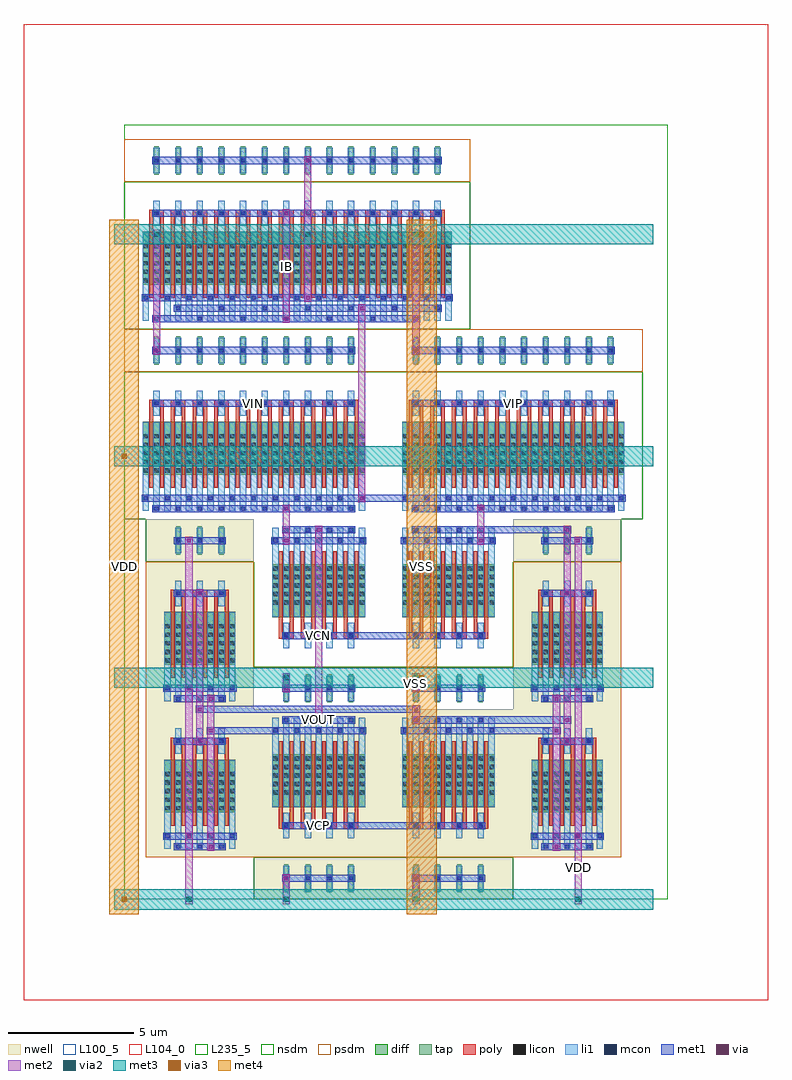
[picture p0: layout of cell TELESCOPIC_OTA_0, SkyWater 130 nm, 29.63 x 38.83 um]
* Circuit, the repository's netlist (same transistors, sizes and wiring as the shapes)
* NGSPICE file created from TELESCOPIC_OTA_0.ext - technology: sky130A

.subckt PMOS_S_26075639_X3_Y2_1774869254 a_230_357# a_200_252# w_0_0#
X0 a_230_357# a_200_252# w_0_0# w_0_0# sky130_fd_pr__pfet_01v8 ad=0.294 pd=2.38 as=0.5565 ps=4.73 w=2.1 l=0.15 M=12
.ends

.subckt SCM_NMOS_72619132_X7_Y1_1774869255 a_200_252# a_402_357# a_147_357#
X0 a_200_252# a_200_252# a_147_357# a_147_357# sky130_fd_pr__nfet_01v8 ad=0.294 pd=2.38 as=0.294 ps=2.38 w=2.1 l=0.15 M=14
X1 a_147_357# a_200_252# a_402_357# a_147_357# sky130_fd_pr__nfet_01v8 ad=0.294 pd=2.38 as=0.294 ps=2.38 w=2.1 l=0.15 M=14
.ends

.subckt NMOS_4T_1818045_X10_Y1_1774869251 a_230_357# a_200_252# a_147_357# a_241_1232#
X0 a_230_357# a_200_252# a_147_357# a_241_1232# sky130_fd_pr__nfet_01v8 ad=0.294 pd=2.38 as=0.294 ps=2.38 w=2.1 l=0.15 M=20
.ends

.subckt NMOS_4T_97331930_X4_Y1_1774869252 a_230_357# a_200_252# a_147_357# a_241_1232#
X0 a_230_357# a_200_252# a_147_357# a_241_1232# sky130_fd_pr__nfet_01v8 ad=0.294 pd=2.38 as=0.294 ps=2.38 w=2.1 l=0.15 M=8
.ends

.subckt PMOS_4T_28463424_X4_Y1_1774869253 a_230_357# a_200_252# a_147_357# w_0_0#
X0 a_230_357# a_200_252# a_147_357# w_0_0# sky130_fd_pr__pfet_01v8 ad=0.294 pd=2.38 as=0.5565 ps=4.73 w=2.1 l=0.15 M=8
.ends

.subckt TELESCOPIC_OTA_0 IB VCN VOUT VIP VIN VCP VSS VDD
XPMOS_S_26075639_X3_Y2_1774869254_0 m1_656_1316# m1_570_1484# VDD PMOS_S_26075639_X3_Y2_1774869254
XPMOS_S_26075639_X3_Y2_1774869254_1 m1_2924_1316# m1_570_1484# VDD PMOS_S_26075639_X3_Y2_1774869254
XSCM_NMOS_72619132_X7_Y1_1774869255_0 IB m1_1860_3164# VSS SCM_NMOS_72619132_X7_Y1_1774869255
XNMOS_4T_1818045_X10_Y1_1774869251_0 m1_1258_2828# VIN m1_1860_3164# VSS NMOS_4T_1818045_X10_Y1_1774869251
XNMOS_4T_1818045_X10_Y1_1774869251_1 m1_2806_2828# VIP m1_1860_3164# VSS NMOS_4T_1818045_X10_Y1_1774869251
XNMOS_4T_97331930_X4_Y1_1774869252_0 VOUT VCN m1_1258_2828# VSS NMOS_4T_97331930_X4_Y1_1774869252
XPMOS_4T_28463424_X4_Y1_1774869253_0 VOUT VCP m1_656_1316# VDD PMOS_4T_28463424_X4_Y1_1774869253
XNMOS_4T_97331930_X4_Y1_1774869252_1 m1_570_1484# VCN m1_2806_2828# VSS NMOS_4T_97331930_X4_Y1_1774869252
XPMOS_4T_28463424_X4_Y1_1774869253_1 m1_570_1484# VCP m1_2924_1316# VDD PMOS_4T_28463424_X4_Y1_1774869253
.ends

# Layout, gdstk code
from math import pi, radians
import gdstk
lib = gdstk.Library(unit=1e-6, precision=1e-09)
def R(c, l, rs):  # rectangles x0, y0, x1, y1
    for r in rs: c.add(gdstk.rectangle(r[:2], r[2:], *l))
def A(c, l, x, y, w, h, nx, ny, dx, dy):  # array of equal rectangles
    R(c, l, [(x+i*dx, y+j*dy, x+i*dx+w, y+j*dy+h) for i in range(nx) for j in range(ny)])
def P(c, l, *ps):  # polygons
    for p in ps: c.add(gdstk.Polygon(p, *l))
nwell = (64, 20)
diff = (65, 20)
tap = (65, 44)
poly = (66, 20)
licon = (66, 44)
li1 = (67, 20)
mcon = (67, 44)
met1 = (68, 20)
via = (68, 44)
met2 = (69, 20)
via2 = (69, 44)
met3 = (70, 20)
via3 = (70, 44)
met4 = (71, 20)
nsdm = (93, 44)
psdm = (94, 20)
L100_5 = (100, 5)
L104_0 = (104, 0)
L235_5 = (235, 5)

scm_nmos_72619132_x7_y1_ = lib.new_cell('SCM_NMOS_72619132_X7_Y1_1774869255')
R(scm_nmos_72619132_x7_y1_, diff, [(0.735,1.785,13.025,3.885)])
A(scm_nmos_72619132_x7_y1_, tap, 1.205, 6.16, 0.17, 1.12, 14, 1, 0.86, 0)
A(scm_nmos_72619132_x7_y1_, poly, 1, 1.26, 0.15, 3.36, 28, 1, 0.43, 0)
A(scm_nmos_72619132_x7_y1_, poly, 1, 4.485, 0.58, 0.27, 14, 1, 0.86, 0)
A(scm_nmos_72619132_x7_y1_, licon, 0.775, 1.865, 0.17, 0.17, 3, 5, 0.43, 0.34)
A(scm_nmos_72619132_x7_y1_, licon, 1.635, 1.865, 0.17, 0.17, 3, 5, 0.43, 0.34)
A(scm_nmos_72619132_x7_y1_, licon, 2.495, 1.865, 0.17, 0.17, 3, 5, 0.43, 0.34)
A(scm_nmos_72619132_x7_y1_, licon, 3.355, 1.865, 0.17, 0.17, 3, 5, 0.43, 0.34)
A(scm_nmos_72619132_x7_y1_, licon, 4.215, 1.865, 0.17, 0.17, 3, 5, 0.43, 0.34)
A(scm_nmos_72619132_x7_y1_, licon, 5.075, 1.865, 0.17, 0.17, 3, 5, 0.43, 0.34)
A(scm_nmos_72619132_x7_y1_, licon, 5.935, 1.865, 0.17, 0.17, 3, 5, 0.43, 0.34)
A(scm_nmos_72619132_x7_y1_, licon, 6.795, 1.865, 0.17, 0.17, 3, 5, 0.43, 0.34)
A(scm_nmos_72619132_x7_y1_, licon, 7.655, 1.865, 0.17, 0.17, 3, 5, 0.43, 0.34)
A(scm_nmos_72619132_x7_y1_, licon, 8.515, 1.865, 0.17, 0.17, 3, 5, 0.43, 0.34)
A(scm_nmos_72619132_x7_y1_, licon, 9.375, 1.865, 0.17, 0.17, 3, 5, 0.43, 0.34)
A(scm_nmos_72619132_x7_y1_, licon, 10.235, 1.865, 0.17, 0.17, 3, 5, 0.43, 0.34)
A(scm_nmos_72619132_x7_y1_, licon, 11.095, 1.865, 0.17, 0.17, 3, 5, 0.43, 0.34)
A(scm_nmos_72619132_x7_y1_, licon, 11.955, 1.865, 0.17, 0.17, 3, 5, 0.43, 0.34)
A(scm_nmos_72619132_x7_y1_, licon, 1.205, 4.535, 0.17, 0.17, 14, 2, 0.86, 2.1)
A(scm_nmos_72619132_x7_y1_, li1, 0.735, 0.335, 0.25, 3.53, 29, 1, 0.43, 0)
A(scm_nmos_72619132_x7_y1_, li1, 1.165, 4.115, 0.25, 1.01, 14, 2, 0.86, 2.1)
A(scm_nmos_72619132_x7_y1_, mcon, 1.205, 0.335, 0.17, 0.17, 7, 1, 1.72, 0)
A(scm_nmos_72619132_x7_y1_, mcon, 2.065, 0.755, 0.17, 0.17, 7, 1, 1.72, 0)
A(scm_nmos_72619132_x7_y1_, mcon, 0.775, 1.175, 0.17, 0.17, 15, 1, 0.86, 0)
A(scm_nmos_72619132_x7_y1_, mcon, 1.205, 4.535, 0.17, 0.17, 14, 2, 0.86, 2.1)
R(scm_nmos_72619132_x7_y1_, met1, [(1.12,0.28,11.78,0.56), (1.98,0.7,12.64,0.98), (0.69,1.12,13.07,1.4), (1.12,4.48,12.64,4.76), (1.12,6.58,12.64,6.86)])
R(scm_nmos_72619132_x7_y1_, via, [(6.375,0.345,6.525,0.495), (7.235,1.185,7.385,1.335), (6.375,4.545,6.525,4.695), (7.235,6.645,7.385,6.795)])
R(scm_nmos_72619132_x7_y1_, met2, [(6.31,0.26,6.59,4.78), (7.17,1.1,7.45,6.88)])
R(scm_nmos_72619132_x7_y1_, nsdm, [(0,0,13.76,5.88)])
R(scm_nmos_72619132_x7_y1_, psdm, [(0,5.88,13.76,7.56)])
R(scm_nmos_72619132_x7_y1_, L100_5, [(0,0,13.76,7.56)])

pmos_s_26075639_x3_y2_17 = lib.new_cell('PMOS_S_26075639_X3_Y2_1774869254')
R(pmos_s_26075639_x3_y2_17, nwell, [(0,0,4.3,13.44)])
R(pmos_s_26075639_x3_y2_17, diff, [(0.735,1.785,3.565,3.885), (0.735,7.665,3.565,9.765)])
A(pmos_s_26075639_x3_y2_17, tap, 1.205, 12.04, 0.17, 1.12, 3, 1, 0.86, 0)
A(pmos_s_26075639_x3_y2_17, poly, 1, 1.26, 0.15, 3.36, 6, 2, 0.43, 5.88)
A(pmos_s_26075639_x3_y2_17, poly, 1, 4.485, 0.58, 0.27, 3, 2, 0.86, 5.88)
A(pmos_s_26075639_x3_y2_17, licon, 0.775, 1.865, 0.17, 0.17, 3, 5, 0.43, 0.34)
A(pmos_s_26075639_x3_y2_17, licon, 1.635, 1.865, 0.17, 0.17, 3, 5, 0.43, 0.34)
A(pmos_s_26075639_x3_y2_17, licon, 2.495, 1.865, 0.17, 0.17, 3, 5, 0.43, 0.34)
A(pmos_s_26075639_x3_y2_17, licon, 1.205, 4.535, 0.17, 0.17, 3, 2, 0.86, 5.88)
A(pmos_s_26075639_x3_y2_17, licon, 0.775, 7.745, 0.17, 0.17, 3, 5, 0.43, 0.34)
A(pmos_s_26075639_x3_y2_17, licon, 1.635, 7.745, 0.17, 0.17, 3, 5, 0.43, 0.34)
A(pmos_s_26075639_x3_y2_17, licon, 2.495, 7.745, 0.17, 0.17, 3, 5, 0.43, 0.34)
R(pmos_s_26075639_x3_y2_17, licon, [(1.205,12.515,1.375,12.685), (1.205,12.515,1.375,12.685), (2.065,12.515,2.235,12.685), (2.065,12.515,2.235,12.685), (2.925,12.515,3.095,12.685), (2.925,12.515,3.095,12.685)])
A(pmos_s_26075639_x3_y2_17, li1, 0.735, 0.335, 0.25, 3.53, 7, 2, 0.43, 5.88)
A(pmos_s_26075639_x3_y2_17, li1, 1.165, 4.115, 0.25, 1.01, 3, 2, 0.86, 5.88)
A(pmos_s_26075639_x3_y2_17, li1, 1.165, 12.095, 0.25, 1.01, 3, 1, 0.86, 0)
A(pmos_s_26075639_x3_y2_17, mcon, 1.205, 0.335, 0.17, 0.17, 3, 2, 0.86, 4.2)
A(pmos_s_26075639_x3_y2_17, mcon, 0.775, 0.755, 0.17, 0.17, 4, 2, 0.86, 5.88)
A(pmos_s_26075639_x3_y2_17, mcon, 1.205, 6.215, 0.17, 0.17, 3, 2, 0.86, 4.2)
A(pmos_s_26075639_x3_y2_17, mcon, 1.205, 12.515, 0.17, 0.17, 3, 1, 0.86, 0)
R(pmos_s_26075639_x3_y2_17, met1, [(1.12,0.28,3.18,0.56), (0.69,0.7,3.61,0.98), (1.12,4.48,3.18,4.76), (1.12,6.16,3.18,6.44), (0.69,6.58,3.61,6.86), (1.12,10.36,3.18,10.64), (1.12,12.46,3.18,12.74)])
A(pmos_s_26075639_x3_y2_17, via, 2.505, 0.765, 0.15, 0.15, 1, 3, 0, 5.88)
R(pmos_s_26075639_x3_y2_17, via, [(1.645,0.345,1.795,0.495), (2.075,4.545,2.225,4.695), (1.645,6.225,1.795,6.375), (2.075,10.425,2.225,10.575)])
R(pmos_s_26075639_x3_y2_17, met2, [(1.58,0.26,1.86,6.46), (2.44,0.68,2.72,12.76), (2.01,4.46,2.29,10.66)])
R(pmos_s_26075639_x3_y2_17, nsdm, [(0,11.76,4.3,13.44)])
R(pmos_s_26075639_x3_y2_17, psdm, [(0,0,4.3,11.76)])
R(pmos_s_26075639_x3_y2_17, L100_5, [(0,0,4.3,13.44)])

nmos_4t_97331930_x4_y1_1 = lib.new_cell('NMOS_4T_97331930_X4_Y1_1774869252')
R(nmos_4t_97331930_x4_y1_1, diff, [(0.735,1.785,4.425,3.885)])
A(nmos_4t_97331930_x4_y1_1, tap, 1.205, 6.16, 0.17, 1.12, 4, 1, 0.86, 0)
A(nmos_4t_97331930_x4_y1_1, poly, 1, 1.26, 0.15, 3.36, 8, 1, 0.43, 0)
A(nmos_4t_97331930_x4_y1_1, poly, 1, 4.485, 0.58, 0.27, 4, 1, 0.86, 0)
A(nmos_4t_97331930_x4_y1_1, licon, 0.775, 1.865, 0.17, 0.17, 3, 5, 0.43, 0.34)
A(nmos_4t_97331930_x4_y1_1, licon, 1.635, 1.865, 0.17, 0.17, 3, 5, 0.43, 0.34)
A(nmos_4t_97331930_x4_y1_1, licon, 2.495, 1.865, 0.17, 0.17, 3, 5, 0.43, 0.34)
A(nmos_4t_97331930_x4_y1_1, licon, 3.355, 1.865, 0.17, 0.17, 3, 5, 0.43, 0.34)
A(nmos_4t_97331930_x4_y1_1, licon, 1.205, 4.535, 0.17, 0.17, 4, 2, 0.86, 2.1)
A(nmos_4t_97331930_x4_y1_1, li1, 0.735, 0.335, 0.25, 3.53, 9, 1, 0.43, 0)
A(nmos_4t_97331930_x4_y1_1, li1, 1.165, 4.115, 0.25, 1.01, 4, 2, 0.86, 2.1)
A(nmos_4t_97331930_x4_y1_1, mcon, 1.205, 0.335, 0.17, 0.17, 4, 2, 0.86, 4.2)
A(nmos_4t_97331930_x4_y1_1, mcon, 0.775, 0.755, 0.17, 0.17, 5, 1, 0.86, 0)
A(nmos_4t_97331930_x4_y1_1, mcon, 1.205, 6.635, 0.17, 0.17, 4, 1, 0.86, 0)
R(nmos_4t_97331930_x4_y1_1, met1, [(1.12,0.28,4.04,0.56), (0.69,0.7,4.47,0.98), (1.12,4.48,4.04,4.76), (1.12,6.58,4.04,6.86)])
R(nmos_4t_97331930_x4_y1_1, nsdm, [(0,0,5.16,5.88)])
R(nmos_4t_97331930_x4_y1_1, psdm, [(0,5.88,5.16,7.56)])
R(nmos_4t_97331930_x4_y1_1, L100_5, [(0,0,5.16,7.56)])

nmos_4t_1818045_x10_y1_1 = lib.new_cell('NMOS_4T_1818045_X10_Y1_1774869251')
R(nmos_4t_1818045_x10_y1_1, diff, [(0.735,1.785,9.585,3.885)])
A(nmos_4t_1818045_x10_y1_1, tap, 1.205, 6.16, 0.17, 1.12, 10, 1, 0.86, 0)
A(nmos_4t_1818045_x10_y1_1, poly, 1, 1.26, 0.15, 3.36, 20, 1, 0.43, 0)
A(nmos_4t_1818045_x10_y1_1, poly, 1, 4.485, 0.58, 0.27, 10, 1, 0.86, 0)
A(nmos_4t_1818045_x10_y1_1, licon, 0.775, 1.865, 0.17, 0.17, 3, 5, 0.43, 0.34)
A(nmos_4t_1818045_x10_y1_1, licon, 1.635, 1.865, 0.17, 0.17, 3, 5, 0.43, 0.34)
A(nmos_4t_1818045_x10_y1_1, licon, 2.495, 1.865, 0.17, 0.17, 3, 5, 0.43, 0.34)
A(nmos_4t_1818045_x10_y1_1, licon, 3.355, 1.865, 0.17, 0.17, 3, 5, 0.43, 0.34)
A(nmos_4t_1818045_x10_y1_1, licon, 4.215, 1.865, 0.17, 0.17, 3, 5, 0.43, 0.34)
A(nmos_4t_1818045_x10_y1_1, licon, 5.075, 1.865, 0.17, 0.17, 3, 5, 0.43, 0.34)
A(nmos_4t_1818045_x10_y1_1, licon, 5.935, 1.865, 0.17, 0.17, 3, 5, 0.43, 0.34)
A(nmos_4t_1818045_x10_y1_1, licon, 6.795, 1.865, 0.17, 0.17, 3, 5, 0.43, 0.34)
A(nmos_4t_1818045_x10_y1_1, licon, 7.655, 1.865, 0.17, 0.17, 3, 5, 0.43, 0.34)
A(nmos_4t_1818045_x10_y1_1, licon, 8.515, 1.865, 0.17, 0.17, 3, 5, 0.43, 0.34)
A(nmos_4t_1818045_x10_y1_1, licon, 1.205, 4.535, 0.17, 0.17, 10, 2, 0.86, 2.1)
A(nmos_4t_1818045_x10_y1_1, li1, 0.735, 0.335, 0.25, 3.53, 21, 1, 0.43, 0)
A(nmos_4t_1818045_x10_y1_1, li1, 1.165, 4.115, 0.25, 1.01, 10, 2, 0.86, 2.1)
A(nmos_4t_1818045_x10_y1_1, mcon, 1.205, 0.335, 0.17, 0.17, 10, 2, 0.86, 4.2)
A(nmos_4t_1818045_x10_y1_1, mcon, 0.775, 0.755, 0.17, 0.17, 11, 1, 0.86, 0)
A(nmos_4t_1818045_x10_y1_1, mcon, 1.205, 6.635, 0.17, 0.17, 10, 1, 0.86, 0)
R(nmos_4t_1818045_x10_y1_1, met1, [(1.12,0.28,9.2,0.56), (0.69,0.7,9.63,0.98), (1.12,4.48,9.2,4.76), (1.12,6.58,9.2,6.86)])
R(nmos_4t_1818045_x10_y1_1, nsdm, [(0,0,10.32,5.88)])
R(nmos_4t_1818045_x10_y1_1, psdm, [(0,5.88,10.32,7.56)])
R(nmos_4t_1818045_x10_y1_1, L100_5, [(0,0,10.32,7.56)])

pmos_4t_28463424_x4_y1_1 = lib.new_cell('PMOS_4T_28463424_X4_Y1_1774869253')
R(pmos_4t_28463424_x4_y1_1, nwell, [(0,0,5.16,7.56)])
R(pmos_4t_28463424_x4_y1_1, diff, [(0.735,1.785,4.425,3.885)])
A(pmos_4t_28463424_x4_y1_1, tap, 1.205, 6.16, 0.17, 1.12, 4, 1, 0.86, 0)
A(pmos_4t_28463424_x4_y1_1, poly, 1, 1.26, 0.15, 3.36, 8, 1, 0.43, 0)
A(pmos_4t_28463424_x4_y1_1, poly, 1, 4.485, 0.58, 0.27, 4, 1, 0.86, 0)
A(pmos_4t_28463424_x4_y1_1, licon, 0.775, 1.865, 0.17, 0.17, 3, 5, 0.43, 0.34)
A(pmos_4t_28463424_x4_y1_1, licon, 1.635, 1.865, 0.17, 0.17, 3, 5, 0.43, 0.34)
A(pmos_4t_28463424_x4_y1_1, licon, 2.495, 1.865, 0.17, 0.17, 3, 5, 0.43, 0.34)
A(pmos_4t_28463424_x4_y1_1, licon, 3.355, 1.865, 0.17, 0.17, 3, 5, 0.43, 0.34)
A(pmos_4t_28463424_x4_y1_1, licon, 1.205, 4.535, 0.17, 0.17, 4, 2, 0.86, 2.1)
A(pmos_4t_28463424_x4_y1_1, li1, 0.735, 0.335, 0.25, 3.53, 9, 1, 0.43, 0)
A(pmos_4t_28463424_x4_y1_1, li1, 1.165, 4.115, 0.25, 1.01, 4, 2, 0.86, 2.1)
A(pmos_4t_28463424_x4_y1_1, mcon, 1.205, 0.335, 0.17, 0.17, 4, 2, 0.86, 4.2)
A(pmos_4t_28463424_x4_y1_1, mcon, 0.775, 0.755, 0.17, 0.17, 5, 1, 0.86, 0)
A(pmos_4t_28463424_x4_y1_1, mcon, 1.205, 6.635, 0.17, 0.17, 4, 1, 0.86, 0)
R(pmos_4t_28463424_x4_y1_1, met1, [(1.12,0.28,4.04,0.56), (0.69,0.7,4.47,0.98), (1.12,4.48,4.04,4.76), (1.12,6.58,4.04,6.86)])
R(pmos_4t_28463424_x4_y1_1, nsdm, [(0,5.88,5.16,7.56)])
R(pmos_4t_28463424_x4_y1_1, psdm, [(0,0,5.16,5.88)])
R(pmos_4t_28463424_x4_y1_1, L100_5, [(0,0,5.16,7.56)])

telescopic_ota_0 = lib.new_cell('TELESCOPIC_OTA_0')
R(telescopic_ota_0, met1, [(6.29,0.7,6.61,0.98), (6.29,0.7,6.61,0.98), (11.45,0.7,11.77,0.98), (11.45,0.7,11.77,0.98), (11.45,0.7,11.77,0.98), (9.03,2.8,11.61,3.08), (3.28,6.58,3.6,6.86), (3.28,6.58,3.6,6.86), (3.44,6.58,6.02,6.86), (14.62,6.58,17.2,6.86), (17.04,6.58,17.36,6.86), (17.04,6.58,17.36,6.86), (7.58,7,7.9,7.28), (7.58,7,7.9,7.28), (11.45,7,11.77,7.28), (11.45,7,11.77,7.28), (11.45,7,11.77,7.28), (11.45,7,11.77,7.28), (11.45,7,11.77,7.28), (11.45,7,11.77,7.28), (14.19,7,17.63,7.28), (17.47,7,17.79,7.28), (17.47,7,17.79,7.28), (17.47,7,17.79,7.28), (17.47,7,17.79,7.28), (2.85,7.42,3.17,7.7), (2.85,7.42,3.17,7.7), (2.85,7.42,3.17,7.7), (2.85,7.42,3.17,7.7), (2.85,7.42,3.17,7.7), (2.85,7.42,3.17,7.7), (3.01,7.42,11.61,7.7), (11.45,7.42,11.77,7.7), (11.45,7.42,11.77,7.7), (11.45,7.42,11.77,7.7), (11.45,7.42,11.77,7.7), (11.45,7.42,11.77,7.7), (11.45,7.42,11.77,7.7), (6.29,8.26,6.61,8.54), (6.29,8.26,6.61,8.54), (6.29,8.26,6.61,8.54), (6.29,8.26,6.61,8.54), (11.45,8.26,11.77,8.54), (11.45,8.26,11.77,8.54), (11.45,8.26,11.77,8.54), (11.45,8.26,11.77,8.54), (11.45,8.26,11.77,8.54), (9.03,10.36,11.61,10.64), (6.29,14.14,6.61,14.42), (6.29,14.14,6.61,14.42), (14.03,14.14,14.35,14.42), (14.03,14.14,14.35,14.42), (7.58,14.56,7.9,14.84), (7.58,14.56,7.9,14.84), (14.19,14.56,17.63,14.84), (17.47,14.56,17.79,14.84), (17.47,14.56,17.79,14.84), (6.29,15.4,6.61,15.68), (6.29,15.4,6.61,15.68), (14.03,15.4,14.35,15.68), (14.03,15.4,14.35,15.68), (9.3,15.82,9.62,16.1), (9.3,15.82,9.62,16.1), (9.3,15.82,9.62,16.1), (9.3,15.82,9.62,16.1), (9.46,15.82,11.18,16.1), (1.13,21.7,1.45,21.98), (1.13,21.7,1.45,21.98), (11.45,21.7,11.77,21.98), (11.45,21.7,11.77,21.98), (11.45,21.7,11.77,21.98), (9.3,23.38,9.62,23.66), (9.3,23.38,9.62,23.66), (9.3,23.38,9.62,23.66), (9.3,23.38,9.62,23.66)])
P(telescopic_ota_0, met1, [(0,0),(0,0),(0,0),(0,0)],
  [(0,0),(0,0),(0,0),(0,0)],
  [(0,0),(0,0),(0,0),(0,0)],
  [(0,0),(0,0),(0,0),(0,0)],
  [(0,0),(0,0),(0,0),(0,0)],
  [(0,0),(0,0),(0,0),(0,0)],
  [(0,0),(0,0),(0,0),(0,0)],
  [(0,0),(0,0),(0,0),(0,0)],
  [(0,0),(0,0),(0,0),(0,0)],
  [(0,0),(0,0),(0,0),(0,0)],
  [(0,0),(0,0),(0,0),(0,0)],
  [(0,0),(0,0),(0,0),(0,0)],
  [(0,0),(0,0),(0,0),(0,0)],
  [(0,0),(0,0),(0,0),(0,0)],
  [(0,0),(0,0),(0,0),(0,0)],
  [(0,0),(0,0),(0,0),(0,0)],
  [(0,0),(0,0),(0,0),(0,0)],
  [(0,0),(0,0),(0,0),(0,0)],
  [(0,0),(0,0),(0,0),(0,0)],
  [(0,0),(0,0),(0,0),(0,0)],
  [(0,0),(0,0),(0,0),(0,0)],
  [(0,0),(0,0),(0,0),(0,0)],
  [(0,0),(0,0),(0,0),(0,0)],
  [(0,0),(0,0),(0,0),(0,0)],
  [(0,0),(0,0),(0,0),(0,0)],
  [(0,0),(0,0),(0,0),(0,0)],
  [(0,0),(0,0),(0,0),(0,0)],
  [(0,0),(0,0),(0,0),(0,0)],
  [(0,0),(0,0),(0,0),(0,0)],
  [(0,0),(0,0),(0,0),(0,0)])
R(telescopic_ota_0, via, [(6.375,0.765,6.525,0.915), (6.375,0.765,6.525,0.915), (11.535,0.765,11.685,0.915), (11.535,0.765,11.685,0.915), (11.535,0.765,11.685,0.915), (3.365,6.645,3.515,6.795), (3.365,6.645,3.515,6.795), (17.125,6.645,17.275,6.795), (17.125,6.645,17.275,6.795), (7.665,7.065,7.815,7.215), (7.665,7.065,7.815,7.215), (11.535,7.065,11.685,7.215), (11.535,7.065,11.685,7.215), (11.535,7.065,11.685,7.215), (11.535,7.065,11.685,7.215), (11.535,7.065,11.685,7.215), (11.535,7.065,11.685,7.215), (17.555,7.065,17.705,7.215), (17.555,7.065,17.705,7.215), (17.555,7.065,17.705,7.215), (17.555,7.065,17.705,7.215), (2.935,7.485,3.085,7.635), (2.935,7.485,3.085,7.635), (2.935,7.485,3.085,7.635), (2.935,7.485,3.085,7.635), (2.935,7.485,3.085,7.635), (2.935,7.485,3.085,7.635), (11.535,7.485,11.685,7.635), (11.535,7.485,11.685,7.635), (11.535,7.485,11.685,7.635), (11.535,7.485,11.685,7.635), (11.535,7.485,11.685,7.635), (11.535,7.485,11.685,7.635), (6.375,8.325,6.525,8.475), (6.375,8.325,6.525,8.475), (6.375,8.325,6.525,8.475), (6.375,8.325,6.525,8.475), (11.535,8.325,11.685,8.475), (11.535,8.325,11.685,8.475), (11.535,8.325,11.685,8.475), (11.535,8.325,11.685,8.475), (11.535,8.325,11.685,8.475), (6.375,14.205,6.525,14.355), (6.375,14.205,6.525,14.355), (14.115,14.205,14.265,14.355), (14.115,14.205,14.265,14.355), (7.665,14.625,7.815,14.775), (7.665,14.625,7.815,14.775), (17.555,14.625,17.705,14.775), (17.555,14.625,17.705,14.775), (6.375,15.465,6.525,15.615), (6.375,15.465,6.525,15.615), (14.115,15.465,14.265,15.615), (14.115,15.465,14.265,15.615), (9.385,15.885,9.535,16.035), (9.385,15.885,9.535,16.035), (9.385,15.885,9.535,16.035), (9.385,15.885,9.535,16.035), (1.215,21.765,1.365,21.915), (1.215,21.765,1.365,21.915), (11.535,21.765,11.685,21.915), (11.535,21.765,11.685,21.915), (11.535,21.765,11.685,21.915), (9.385,23.445,9.535,23.595), (9.385,23.445,9.535,23.595), (9.385,23.445,9.535,23.595), (9.385,23.445,9.535,23.595)])
R(telescopic_ota_0, met2, [(2.44,-0.185,2.72,0.185), (2.44,-0.185,2.72,0.185), (2.44,-0.185,2.72,0.185), (2.44,-0.185,2.72,0.185), (6.31,-0.185,6.59,0.185), (6.31,-0.185,6.59,0.185), (11.47,-0.185,11.75,0.185), (11.47,-0.185,11.75,0.185), (11.47,-0.185,11.75,0.185), (17.92,-0.185,18.2,0.185), (17.92,-0.185,18.2,0.185), (17.92,-0.185,18.2,0.185), (17.92,-0.185,18.2,0.185), (17.92,-0.185,18.2,0.185), (2.44,0,2.72,2.52), (6.31,0,6.59,0.84), (11.47,0,11.75,0.84), (17.92,0,18.2,2.52), (6.31,0.68,6.59,1), (6.31,0.68,6.59,1), (11.47,0.68,11.75,1), (11.47,0.68,11.75,1), (11.47,0.68,11.75,1), (3.3,6.56,3.58,6.88), (3.3,6.56,3.58,6.88), (17.06,6.56,17.34,6.88), (17.06,6.56,17.34,6.88), (7.6,6.98,7.88,7.3), (7.6,6.98,7.88,7.3), (11.47,6.98,11.75,7.3), (11.47,6.98,11.75,7.3), (11.47,6.98,11.75,7.3), (11.47,6.98,11.75,7.3), (11.47,6.98,11.75,7.3), (11.47,6.98,11.75,7.3), (17.49,6.98,17.77,7.3), (17.49,6.98,17.77,7.3), (17.49,6.98,17.77,7.3), (17.49,6.98,17.77,7.3), (7.6,7.14,7.88,14.7), (11.47,7.14,11.75,7.56), (2.87,7.4,3.15,7.72), (2.87,7.4,3.15,7.72), (2.87,7.4,3.15,7.72), (2.87,7.4,3.15,7.72), (2.87,7.4,3.15,7.72), (2.87,7.4,3.15,7.72), (11.47,7.4,11.75,7.72), (11.47,7.4,11.75,7.72), (11.47,7.4,11.75,7.72), (11.47,7.4,11.75,7.72), (11.47,7.4,11.75,7.72), (11.47,7.4,11.75,7.72), (6.31,8.24,6.59,8.56), (6.31,8.24,6.59,8.56), (6.31,8.24,6.59,8.56), (6.31,8.24,6.59,8.56), (11.47,8.24,11.75,8.56), (11.47,8.24,11.75,8.56), (11.47,8.24,11.75,8.56), (11.47,8.24,11.75,8.56), (11.47,8.24,11.75,8.56), (6.31,8.4,6.59,8.82), (11.47,8.4,11.75,8.82), (6.31,8.635,6.59,9.005), (6.31,8.635,6.59,9.005), (6.31,8.635,6.59,9.005), (6.31,8.635,6.59,9.005), (11.47,8.635,11.75,9.005), (11.47,8.635,11.75,9.005), (11.47,8.635,11.75,9.005), (11.47,8.635,11.75,9.005), (11.47,8.635,11.75,9.005), (17.49,12.18,17.77,14.7), (6.31,14.12,6.59,14.44), (6.31,14.12,6.59,14.44), (14.05,14.12,14.33,14.44), (14.05,14.12,14.33,14.44), (6.31,14.28,6.59,15.54), (14.05,14.28,14.33,15.54), (7.6,14.54,7.88,14.86), (7.6,14.54,7.88,14.86), (17.49,14.54,17.77,14.86), (17.49,14.54,17.77,14.86), (6.31,15.38,6.59,15.7), (6.31,15.38,6.59,15.7), (14.05,15.38,14.33,15.7), (14.05,15.38,14.33,15.7), (9.32,15.8,9.6,16.12), (9.32,15.8,9.6,16.12), (9.32,15.8,9.6,16.12), (9.32,15.8,9.6,16.12), (9.32,15.96,9.6,23.52), (1.15,21.68,1.43,22), (1.15,21.68,1.43,22), (11.47,21.68,11.75,22), (11.47,21.68,11.75,22), (11.47,21.68,11.75,22), (1.15,21.84,1.43,26.46), (11.47,21.84,11.75,26.46), (9.32,23.36,9.6,23.68), (9.32,23.36,9.6,23.68), (9.32,23.36,9.6,23.68), (9.32,23.36,9.6,23.68), (1.15,26.275,1.43,26.645), (1.15,26.275,1.43,26.645), (7.17,26.275,7.45,26.645), (7.17,26.275,7.45,26.645), (7.17,26.275,7.45,26.645), (7.17,26.275,7.45,26.645), (7.17,26.275,7.45,26.645), (7.17,26.275,7.45,26.645), (11.47,26.275,11.75,26.645), (11.47,26.275,11.75,26.645), (11.47,26.275,11.75,26.645)])
P(telescopic_ota_0, met2, [(0,0),(0,0),(0,0),(0,0)],
  [(0,0),(0,0),(0,0),(0,0)],
  [(0,0),(0,0),(0,0),(0,0)],
  [(0,0),(0,0),(0,0),(0,0)],
  [(0,0),(0,0),(0,0),(0,0)],
  [(0,0),(0,0),(0,0),(0,0)],
  [(0,0),(0,0),(0,0),(0,0)],
  [(0,0),(0,0),(0,0),(0,0)],
  [(0,0),(0,0),(0,0),(0,0)])
R(telescopic_ota_0, via2, [(2.48,-0.1,2.68,0.1), (2.48,-0.1,2.68,0.1), (2.48,-0.1,2.68,0.1), (2.48,-0.1,2.68,0.1), (6.35,-0.1,6.55,0.1), (6.35,-0.1,6.55,0.1), (11.51,-0.1,11.71,0.1), (11.51,-0.1,11.71,0.1), (11.51,-0.1,11.71,0.1), (17.96,-0.1,18.16,0.1), (17.96,-0.1,18.16,0.1), (17.96,-0.1,18.16,0.1), (17.96,-0.1,18.16,0.1), (17.96,-0.1,18.16,0.1), (6.35,8.72,6.55,8.92), (6.35,8.72,6.55,8.92), (6.35,8.72,6.55,8.92), (6.35,8.72,6.55,8.92), (11.51,8.72,11.71,8.92), (11.51,8.72,11.71,8.92), (11.51,8.72,11.71,8.92), (11.51,8.72,11.71,8.92), (11.51,8.72,11.71,8.92), (1.19,26.36,1.39,26.56), (1.19,26.36,1.39,26.56), (7.21,26.36,7.41,26.56), (7.21,26.36,7.41,26.56), (7.21,26.36,7.41,26.56), (7.21,26.36,7.41,26.56), (7.21,26.36,7.41,26.56), (7.21,26.36,7.41,26.56), (11.51,26.36,11.71,26.56), (11.51,26.36,11.71,26.56), (11.51,26.36,11.71,26.56)])
A(telescopic_ota_0, met3, -0.4, -0.4, 4.24, 0.8, 3, 4, 3.44, 8.82)
A(telescopic_ota_0, met3, 9.92, -0.4, 2.32, 0.8, 1, 4, 0, 8.82)
A(telescopic_ota_0, met3, 11.44, -0.4, 2.72, 0.8, 1, 4, 0, 8.82)
A(telescopic_ota_0, met3, 13.36, -0.4, 4.24, 0.8, 1, 4, 0, 8.82)
A(telescopic_ota_0, met3, 16.8, -0.4, 4.24, 0.8, 1, 4, 0, 8.82)
R(telescopic_ota_0, met3, [(-0.165,-0.4,0.165,0.4), (2.415,-0.4,2.745,0.4), (2.415,-0.4,2.745,0.4), (2.415,-0.4,2.745,0.4), (2.415,-0.4,2.745,0.4), (6.285,-0.4,6.615,0.4), (6.285,-0.4,6.615,0.4), (11.445,-0.4,11.775,0.4), (11.445,-0.4,11.775,0.4), (11.445,-0.4,11.775,0.4), (17.895,-0.4,18.225,0.4), (17.895,-0.4,18.225,0.4), (17.895,-0.4,18.225,0.4), (17.895,-0.4,18.225,0.4), (17.895,-0.4,18.225,0.4), (6.285,8.42,6.615,9.22), (6.285,8.42,6.615,9.22), (6.285,8.42,6.615,9.22), (6.285,8.42,6.615,9.22), (11.445,8.42,11.775,9.22), (11.445,8.42,11.775,9.22), (11.445,8.42,11.775,9.22), (11.445,8.42,11.775,9.22), (11.445,8.42,11.775,9.22), (11.675,8.42,12.005,9.22), (-0.165,17.24,0.165,18.04), (1.125,26.06,1.455,26.86), (1.125,26.06,1.455,26.86), (7.145,26.06,7.475,26.86), (7.145,26.06,7.475,26.86), (7.145,26.06,7.475,26.86), (7.145,26.06,7.475,26.86), (7.145,26.06,7.475,26.86), (7.145,26.06,7.475,26.86), (11.445,26.06,11.775,26.86), (11.445,26.06,11.775,26.86), (11.445,26.06,11.775,26.86), (11.675,26.06,12.005,26.86)])
R(telescopic_ota_0, via3, [(-0.1,-0.1,0.1,0.1), (11.74,8.72,11.94,8.92), (-0.1,17.54,0.1,17.74), (11.74,26.36,11.94,26.56)])
A(telescopic_ota_0, met4, -0.59, -0.59, 1.18, 10, 1, 3, 0, 8.82)
A(telescopic_ota_0, met4, 11.25, -0.59, 1.18, 10, 1, 3, 0, 8.82)
R(telescopic_ota_0, met4, [(-0.59,-0.165,0.59,0.165), (11.25,8.655,12.43,8.985), (-0.59,17.475,0.59,17.805), (11.25,26.295,12.43,26.625)])
R(telescopic_ota_0, L104_0, [(-4,-4,25.63,34.83)])
R(telescopic_ota_0, L235_5, [(0,0,21.63,30.83)])
telescopic_ota_0.add(gdstk.Reference(scm_nmos_72619132_x7_y1_, (0,22.68)))
telescopic_ota_0.add(gdstk.Reference(pmos_s_26075639_x3_y2_17, (15.48,1.68)))
telescopic_ota_0.add(gdstk.Reference(pmos_s_26075639_x3_y2_17, (5.16,1.68), rotation=pi, x_reflection=True))
telescopic_ota_0.add(gdstk.Reference(nmos_4t_97331930_x4_y1_1, (10.32,15.12), x_reflection=True))
telescopic_ota_0.add(gdstk.Reference(nmos_4t_97331930_x4_y1_1, (10.32,15.12), rotation=pi))
telescopic_ota_0.add(gdstk.Reference(nmos_4t_1818045_x10_y1_1, (20.64,15.12), rotation=pi, x_reflection=True))
telescopic_ota_0.add(gdstk.Reference(nmos_4t_1818045_x10_y1_1, (0,15.12)))
telescopic_ota_0.add(gdstk.Reference(pmos_4t_28463424_x4_y1_1, (15.48,7.56), rotation=pi))
telescopic_ota_0.add(gdstk.Reference(pmos_4t_28463424_x4_y1_1, (5.16,7.56), x_reflection=True))
telescopic_ota_0.add(gdstk.Label('IB', (6.45,25.2), layer=69, texttype=5))
telescopic_ota_0.add(gdstk.Label('VCN', (7.74,10.5), layer=68, texttype=5))
telescopic_ota_0.add(gdstk.Label('VOUT', (7.74,7.14), layer=68, texttype=5))
telescopic_ota_0.add(gdstk.Label('VIP', (15.48,19.74), layer=68, texttype=5))
telescopic_ota_0.add(gdstk.Label('VIN', (5.16,19.74), layer=68, texttype=5))
telescopic_ota_0.add(gdstk.Label('VCP', (7.74,2.94), layer=68, texttype=5))
telescopic_ota_0.add(gdstk.Label('VSS', (11.84,13.23), layer=71, texttype=5))
telescopic_ota_0.add(gdstk.Label('VSS', (11.84,13.23), layer=71, texttype=5))
telescopic_ota_0.add(gdstk.Label('VSS', (11.84,13.23), layer=71, texttype=5))
telescopic_ota_0.add(gdstk.Label('VSS', (11.61,8.61), layer=69, texttype=5))
telescopic_ota_0.add(gdstk.Label('VSS', (11.84,13.23), layer=71, texttype=5))
telescopic_ota_0.add(gdstk.Label('VSS', (11.84,13.23), layer=71, texttype=5))
telescopic_ota_0.add(gdstk.Label('VSS', (11.84,13.23), layer=71, texttype=5))
telescopic_ota_0.add(gdstk.Label('VSS', (11.84,13.23), layer=71, texttype=5))
telescopic_ota_0.add(gdstk.Label('VSS', (11.84,13.23), layer=71, texttype=5))
telescopic_ota_0.add(gdstk.Label('VSS', (11.84,13.23), layer=71, texttype=5))
telescopic_ota_0.add(gdstk.Label('VSS', (11.84,13.23), layer=71, texttype=5))
telescopic_ota_0.add(gdstk.Label('VSS', (11.84,13.23), layer=71, texttype=5))
telescopic_ota_0.add(gdstk.Label('VSS', (11.84,13.23), layer=71, texttype=5))
telescopic_ota_0.add(gdstk.Label('VSS', (11.84,13.23), layer=71, texttype=5))
telescopic_ota_0.add(gdstk.Label('VSS', (11.84,13.23), layer=71, texttype=5))
telescopic_ota_0.add(gdstk.Label('VDD', (18.06,1.26), layer=69, texttype=5))
telescopic_ota_0.add(gdstk.Label('VDD', (0,13.23), layer=71, texttype=5))
telescopic_ota_0.add(gdstk.Label('VDD', (0,13.23), layer=71, texttype=5))
telescopic_ota_0.add(gdstk.Label('VDD', (0,13.23), layer=71, texttype=5))
telescopic_ota_0.add(gdstk.Label('VDD', (0,13.23), layer=71, texttype=5))
telescopic_ota_0.add(gdstk.Label('VDD', (0,13.23), layer=71, texttype=5))
telescopic_ota_0.add(gdstk.Label('VDD', (0,13.23), layer=71, texttype=5))
telescopic_ota_0.add(gdstk.Label('VDD', (0,13.23), layer=71, texttype=5))
telescopic_ota_0.add(gdstk.Label('VDD', (0,13.23), layer=71, texttype=5))
telescopic_ota_0.add(gdstk.Label('VDD', (0,13.23), layer=71, texttype=5))
telescopic_ota_0.add(gdstk.Label('VDD', (0,13.23), layer=71, texttype=5))

lib.write_gds('TELESCOPIC_OTA_0.gds')
